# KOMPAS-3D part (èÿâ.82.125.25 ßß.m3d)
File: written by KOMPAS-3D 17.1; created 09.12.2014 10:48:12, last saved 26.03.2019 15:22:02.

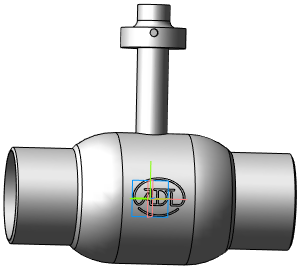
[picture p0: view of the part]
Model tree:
1. Операция без истории:5  (labels: Сталь 20  ГОСТ 1050-88)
